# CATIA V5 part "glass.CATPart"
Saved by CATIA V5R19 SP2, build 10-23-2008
Part number: glass
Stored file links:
  C:\BEHROOZ\catia learning\tarh haye mashin\hb\glass.CATPart

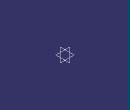
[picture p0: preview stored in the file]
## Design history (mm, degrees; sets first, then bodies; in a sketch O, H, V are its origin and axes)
Body1 (main body)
